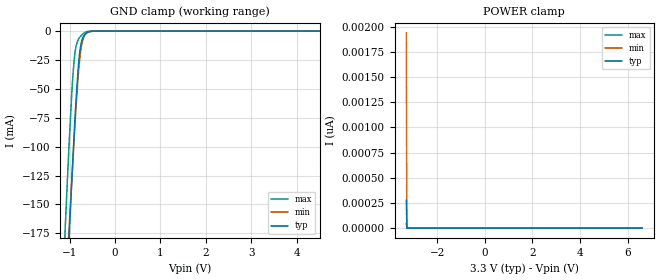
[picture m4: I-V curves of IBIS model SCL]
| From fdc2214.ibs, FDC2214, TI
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|   Model
[Model]   SCL
Model_type   Input
Vinl = 0.99
Vinh = 2.31
|   typ   min   max
C_comp   0.814pF   0.790pF   0.843pF
[Voltage Range]   3.3   2.7   3.6
[Temperature Range]   27   125   -40
[Power Clamp Reference]   3.3   2.7   3.6
[GND Clamp Reference]   0   0   0
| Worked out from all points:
|   GND clamp passes 1 mA (typ) near -0.59 V on its own axis
[GND Clamp]
|   Voltage   I(typ)   I(min)   I(max)
-3.3V     -2.398A    -1.758A    -2.318A
-1.171V   -324.6mA   -281.3mA   -238.7mA
-1.063V   -225.9mA   -206.3mA   -141.8mA
-1.013V   -182.5mA   -172.2mA   -100.5mA
-1.003V   -174mA     -165.4mA   -92.57mA
-943.8mV  -124.4mA   -124.5mA   -49.45mA
-894.3mV  -85.85mA   -90.5mA    -23.43mA
-854.7mV  -58.16mA   -64.23mA   -12.55mA
-805.2mV  -30.1mA    -36.78mA   -7.15mA
-735.9mV  -9.043mA   -12.63mA   -3.541mA
-646.8mV  -2.343mA   -2.572mA   -918.9uA
6.6V      0A         0A         0A
[POWER Clamp]
|   Voltage   I(typ)   I(min)   I(max)
-3.3V     276.1pA    1.937nA    44.09pA
-3.28V    0A         0A         0A
-3.27V    0A         0A         0A
6.6V      0A         0A         0A
